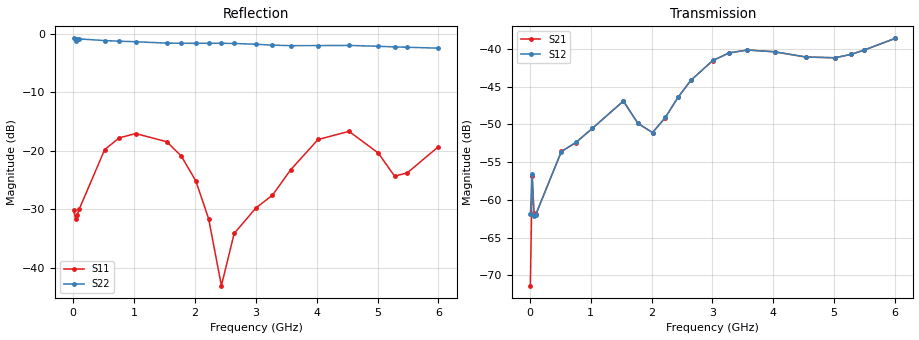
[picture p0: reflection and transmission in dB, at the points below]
!Agilent Technologies,E8364B,MY43040528,A.07.50.67
!Agilent E8364B: A.07.50.67
!Date: Sunday, September 28, 2025 22:04:49
!Correction: S11(Full 2 Port(1,2))
!S21(Full 2 Port(1,2))
!S12(Full 2 Port(1,2))
!S22(Full 2 Port(1,2))
!S2P File: Measurements: S11, S21, S12, S22:
# Hz S  dB  R 50
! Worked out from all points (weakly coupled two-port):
!   201 points, 10 MHz to 6 GHz, reference 50 ohm
!   highest |S21| = -38.62 dB at 6 GHz (marker M1); lowest = -71.4 dB at 10 MHz (marker M2)
!   lowest |S11| = -43.1 dB at 2.436 GHz (marker M3), VSWR 1.01, Z = 50 + j0.702 ohm
!   |S11| at or under -10 dB: start of sweep to end of sweep
!   |S22| runs from -2.5 to -0.8 dB; largest |S21 - S12| = 0.00091
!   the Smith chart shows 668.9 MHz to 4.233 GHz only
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1e7  -30.13 -44.4  -71.38 138.8  -61.91 33.2  -0.82 180.0
3.995e7  -31.63 -32.3  -56.91 11.8  -56.58 8.9  -1.30 -176.9
6.99e7  -30.95 -39.4  -61.77 8.4  -62.09 5.9  -0.89 174.4
9.985e7  -30.03 -50.1  -61.91 24.7  -61.99 25.3  -0.91 169.8
5.1915e8  -19.82 -135.4  -53.60 -14.6  -53.62 -15.0  -1.20 120.5
7.5875e8  -17.82 -168.8  -52.42 -41.7  -52.40 -41.9  -1.30 93.9
1.0283e9  -17.09 158.5  -50.54 -70.7  -50.54 -70.6  -1.40 63.7
1.53745e9  -18.48 100.5  -46.93 175.1  -46.92 175.1  -1.63 6.2
1.77705e9  -20.93 74.0  -49.88 102.5  -49.89 102.6  -1.66 -21.5
2.01665e9  -25.20 50.4  -51.10 23.1  -51.10 23.2  -1.67 -49.9
2.2263e9  -31.65 38.0  -49.12 -38.5  -49.09 -38.5  -1.66 -75.0
2.43595e9  -43.08 89.3  -46.42 -86.9  -46.42 -86.7  -1.66 -100.5
2.6456e9  -34.16 141.8  -44.17 -128.0  -44.20 -127.9  -1.69 -126.1
3.005e9  -29.77 134.5  -41.56 168.8  -41.55 168.8  -1.83 -170.2
3.27455e9  -27.63 138.8  -40.55 124.8  -40.55 124.9  -1.97 156.7
3.57405e9  -23.27 133.2  -40.16 79.5  -40.16 79.5  -2.07 120.3
4.0233e9  -18.10 98.2  -40.40 18.4  -40.40 18.5  -2.05 67.3
4.53245e9  -16.71 45.4  -41.09 -42.0  -41.09 -41.9  -2.03 9.3
5.01165e9  -20.41 3.0  -41.19 -91.6  -41.19 -91.4  -2.17 -44.9
5.2812e9  -24.38 4.3  -40.73 -119.4  -40.73 -119.2  -2.28 -75.7
5.49085e9  -23.78 20.5  -40.17 -142.2  -40.18 -142.0  -2.34 -99.7
6e9  -19.33 -17.6  -38.62 155.7  -38.63 155.8  -2.49 -159.4
